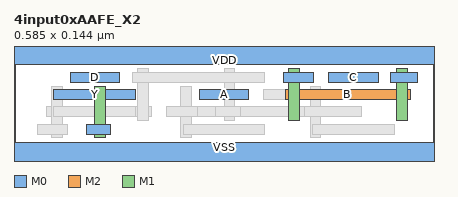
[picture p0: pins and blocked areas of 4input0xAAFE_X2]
MACRO 4input0xAAFE_X2
  CLASS CORE ;
  ORIGIN 0 0 ;
  FOREIGN 4input0xAAFE_X2 0 0 ;
  SIZE 0.5850 BY 0.1440 ;
  SYMMETRY X Y ;
  SITE coresite ;
  PIN A
    DIRECTION INPUT ;
    USE SIGNAL ;
    PORT
      LAYER M0 ;
        RECT 0.2580 0.0770 0.3270 0.0910 ;
    END
  END A
  PIN B
    DIRECTION INPUT ;
    USE SIGNAL ;
    PORT
      LAYER M2 ;
        RECT 0.3780 0.0770 0.5520 0.0910 ;
      LAYER M1 ;
        RECT 0.3825 0.0480 0.3975 0.1200 ;
        RECT 0.5325 0.0480 0.5475 0.1200 ;
      LAYER M0 ;
        RECT 0.5250 0.1010 0.5625 0.1150 ;
        RECT 0.3750 0.1010 0.4170 0.1150 ;
    END
  END B
  PIN C
    DIRECTION INPUT ;
    USE SIGNAL ;
    PORT
      LAYER M0 ;
        RECT 0.4380 0.1010 0.5070 0.1150 ;
    END
  END C
  PIN D
    DIRECTION INPUT ;
    USE SIGNAL ;
    PORT
      LAYER M0 ;
        RECT 0.0780 0.1010 0.1470 0.1150 ;
    END
  END D
  PIN Y
    DIRECTION OUTPUT ;
    USE SIGNAL ;
    PORT
      LAYER M1 ;
        RECT 0.1125 0.0240 0.1275 0.0960 ;
      LAYER M0 ;
        RECT 0.0555 0.0770 0.1695 0.0910 ;
        RECT 0.1005 0.0290 0.1350 0.0430 ;
    END
  END Y
  PIN VDD
    DIRECTION INOUT ;
    USE POWER ;
    SHAPE ABUTMENT ;
    PORT
      LAYER M0 ;
        RECT 0.0000 0.1260 0.5850 0.1620 ;
    END
  END VDD
  PIN VSS
    DIRECTION INOUT ;
    USE GROUND ;
    SHAPE ABUTMENT ;
    PORT
      LAYER M0 ;
        RECT 0.0000 -0.0180 0.5850 0.0180 ;
    END
  END VSS
  OBS
    LAYER M2 ;
      RECT 0.0450 0.0530 0.1920 0.0670 ;
      RECT 0.2250 0.0530 0.4320 0.0670 ;
    LAYER V1 ;
      RECT 0.0530 0.0530 0.0670 0.0670 ;
      RECT 0.1730 0.0530 0.1870 0.0670 ;
      RECT 0.2330 0.0530 0.2470 0.0670 ;
      RECT 0.4130 0.0530 0.4270 0.0670 ;
      RECT 0.3830 0.0770 0.3970 0.0910 ;
      RECT 0.5330 0.0770 0.5470 0.0910 ;
    LAYER M1 ;
      RECT 0.0525 0.0240 0.0675 0.0960 ;
      RECT 0.2325 0.0240 0.2475 0.0960 ;
      RECT 0.4125 0.0240 0.4275 0.0960 ;
      RECT 0.1725 0.0480 0.1875 0.1200 ;
      RECT 0.2925 0.0480 0.3075 0.1200 ;
    LAYER V0 ;
      RECT 0.1130 0.0770 0.1270 0.0910 ;
      RECT 0.1130 0.0290 0.1270 0.0430 ;
      RECT 0.0530 0.0290 0.0670 0.0430 ;
      RECT 0.1730 0.1010 0.1870 0.1150 ;
      RECT 0.2930 0.1010 0.3070 0.1150 ;
      RECT 0.2930 0.0530 0.3070 0.0670 ;
      RECT 0.2330 0.0530 0.2470 0.0670 ;
      RECT 0.4130 0.0770 0.4270 0.0910 ;
      RECT 0.4130 0.0530 0.4270 0.0670 ;
      RECT 0.3830 0.1010 0.3970 0.1150 ;
      RECT 0.5330 0.1010 0.5470 0.1150 ;
    LAYER M0 ;
      RECT 0.0330 0.0290 0.0750 0.0430 ;
      RECT 0.2355 0.0290 0.3495 0.0430 ;
      RECT 0.4155 0.0290 0.5295 0.0430 ;
      RECT 0.0555 0.0530 0.1695 0.0670 ;
      RECT 0.2130 0.0530 0.2550 0.0670 ;
      RECT 0.2805 0.0530 0.3150 0.0670 ;
      RECT 0.4050 0.0530 0.4845 0.0670 ;
      RECT 0.3480 0.0770 0.5295 0.0910 ;
      RECT 0.1650 0.1010 0.3495 0.1150 ;
  END
END 4input0xAAFE_X2
